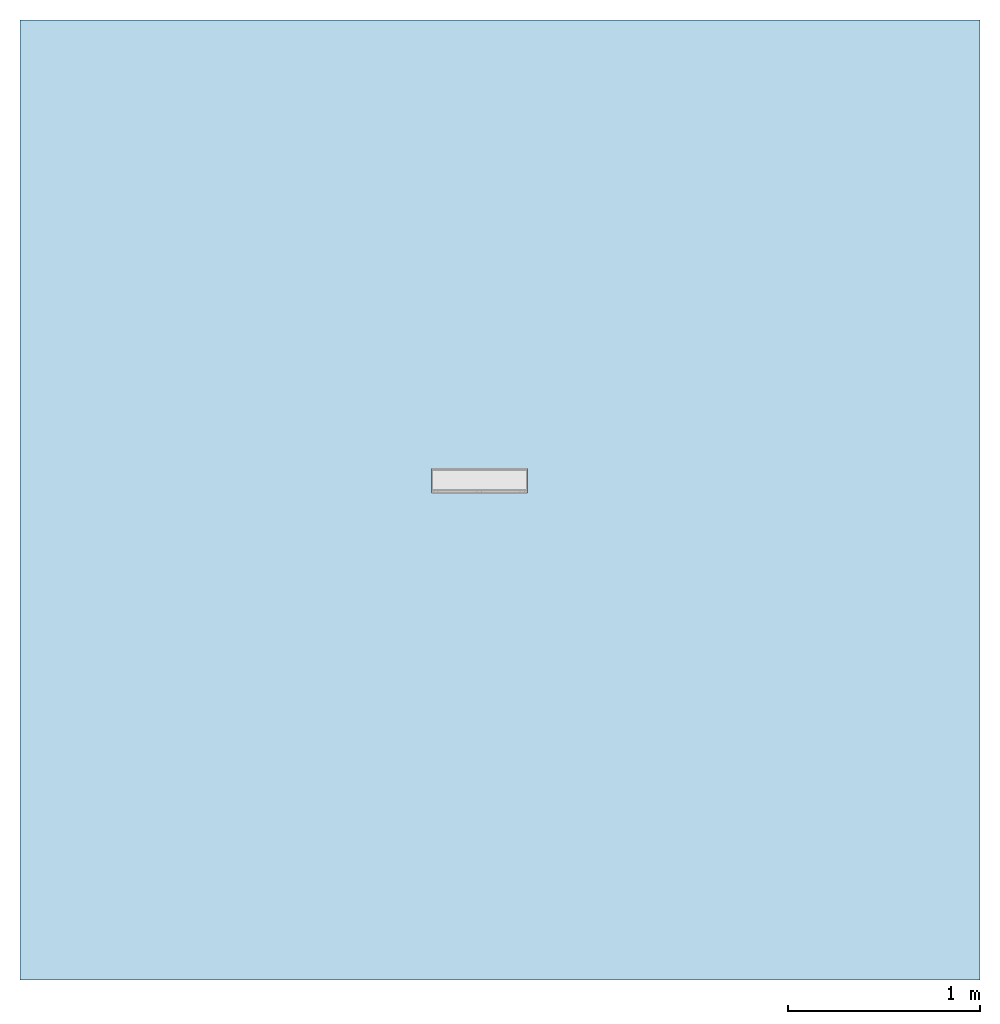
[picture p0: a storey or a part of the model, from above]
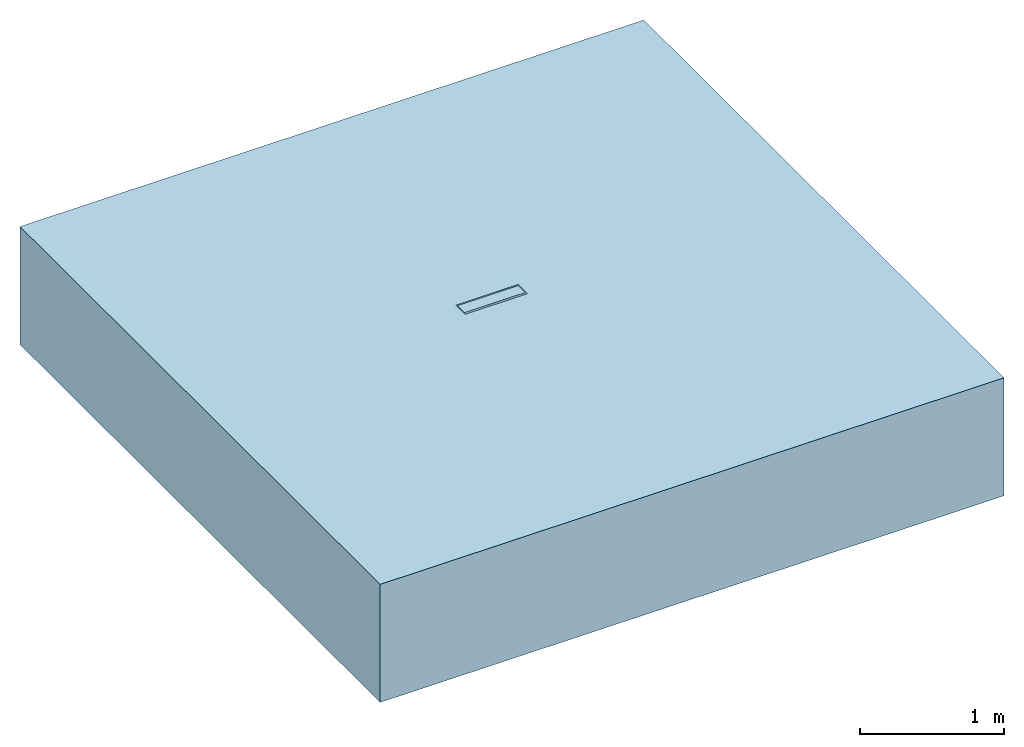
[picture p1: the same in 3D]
Properties of the parts of a building model (IFC2X3)

# File
Description: ViewDefinition [CoordinationView]
File name: 23410 - Universal Sump Unit - 500mm LG.ifc
Time: 2013-10-31T17:35:49
Written by: Autodesk Revit 2013
Made in: 20120221_2030(x64)

# IfcProject, Project Number
LongName: Project Name; Phase: Project Status

# IfcSite, Default
RefLatitude: 42, 21, 30, 344238; RefLongitude: -71, -3, -35, -194702; RefElevation: 0 mm

# IfcBuilding
Pset_BuildingCommon - NumberOfStoreys: 1
Other - Project Address: ## Street City, State Zip; Client Name: Owner; Project Number: Project Number; Project Name: Project Name; Project Issue Date: Issue Date; Project Status: Project Status

# IfcBuildingStorey, Level 1
LongName: Level 1; Elevation: 0 mm
Constraints - Elevation Base: 0; Elevation: 0 mm
Graphics - Color: 0; Symbol: M_Level Head - Circle: M_Level Head - Circle; Symbol at End 1 Default: no; Line Pattern: Center; Symbol at End 2 Default: yes; Line Weight: 1
Identity Data - Building Story: yes; Name: Level 1; Structural: no
Dimensions - Computation Height: 0 mm

# IfcBuildingElementProxy: 23410 - Universal Sump Unit - 500mm LG, Civil-Drainage-Channel-ACO-MultiDrain-M100D-Brickslot-Channel-System:23410 - Universal Sump Unit - 500mm LG:23410 - Universal Sump Unit - 500mm LG:196059
In: Level 1
Material: Vienite® Synthetic Resin Concrete, Phenolic Resin, Plastic, Opaque Black, Steel, Galvanized
Materials and Finishes - Edge Rail Colour: Silver; Channel Colour: Brown; Edge Rail Material: Steel; Channel Material: Vienite® Synthetic Resin Concrete; Edge Rail Finish: Pre-galvanised
Constraints - Level: Level: Level 1; Moves With Nearby Elements: no
Construction - 23460_Load Class C250_Brickslot Grating_Galvanized Steel_1000mm Long: no; 23404_Universal Endcap (Male End): no; 23462_Load Class C250_Brickslot Access Unit_Galvanised Steel_500mm Long: no; 23465_Load Class D400_Brickslot Grating_Galvanized Steel_1000mm Long: no; 23461_Load Class C250_Brickslot Grating_Galvanized Steel_500mm Long: no; 23404_Universal Endcap (Female End): no; 23467_Load Class D400_Brickslot Access Unit_Galvanised Steel_500mm Long: yes; 23466_Load Class D400_Brickslot Grating_Galvanized Steel_500mm Long: no; Constant Depth Junction Channel: no; 23410_Sump Unit: yes; Sloping Channel: no; Shallow Depth Channel with seal: no; Shallow Depth Channel: no; Constant Depth Channel: no
Dimensions - Brickslot Void Length: 1000 mm; Custom_Void_length: 500 mm; FloorCut_Length: -500 mm; Brickslot Void Depth: 6000 mm; EndCap Position: 500 mm; Volume: 16336718 mm3; Brickslot Access Unit Void Bottom Depth: -105 mm; Brickslot Access Unit Void Depth: 0 mm; Length: 1000 mm; FloorCut_Depth: 635 mm; Depth: 150 mm; SlopingOverallDepth: 245 mm; FloorCut_Width: 135 mm; GratingLength: -1000 mm; InvDepth: 80 mm; Floor Cut Gap: 105 mm; ShallowOverallDepth: 75 mm; SlopingEndInvertDepth: 180 mm; Brickslot Access Unit Floor Cut Length: 500 mm; EndCap_Height: 250 mm; Access_Custom_Void_Length: 0 mm; Length Drain: -500 mm; ShallowInvDepth: 55 mm; SlopingEndOverallDepth: 250 mm; SlopingInvertDepth: 175 mm
Phasing - Phase Created: New Construction
Pset_BuildingElementProxyCommon - Reference: 23410 - Universal Sump Unit - 500mm LG
Model Properties - Brickslot Access Unit Product code 23467: Load Class D400 - Brickslot Access Unit Galvanised Steel - 500mm long x 105mm high - 10mm Slot - Intake area - 10000mm²/m - 6.4 Kg; Brickslot Access Unit Product code 23462: Load Class C250 - Brickslot Access Unit Galvanised Steel - 500mm long x 105mm high - 10mm Slot - Intake area - 10000mm²/m - 6.4 Kg; Brickslot Grating Product code 23465: N/A; Brickslot Grating Product code 23466: N/A; End Cap Product code 23404: No 306 Universal End Cap - 135mm wide x 300mm long - Spigot Ø110mm x 50mm long - Silver - Polypropylene - 0.16kg; Brickslot Grating Product code 23460: N/A; Brickslot Grating Product code 23461: N/A
Identity Data - e-mail Sales: customersupport@aco.co.uk; Assembly Code: D2040; Product brochure: http://www.aco.co.uk/download.php?id=173; OmniClass Title: Rainwater Removal; Installation guidelines: http://www.aco.co.uk/download.php?id=173; Watermarked With: BIM Manager Premium Suite; OmniClass Number: 23.70.50.24; e-mail Technical: technical@aco.co.uk; Model Description: Channel drainage system; URL: www.aco.co.uk; Watermark 2: This file is water marked and users are prohibited to reproduce, adapt, distribute this information; Address: ACO Business Park, Hitchin Road, Shefford, Bedfordshire, United Kingdom SG17 5TE; Maintenance guidelines: http://www.aco.co.uk/download.php?id=173; Type Comments: ACO MultiDrain M100D Sump Unit 500mm Long; Model: ACO MultiDrain MD Brickslot- M100D; Telephone: +44 (0)1462 816666; Product Page URL: http://www.aco.co.uk/product_detail.php?id=58; Watermark 1: This file is the property of ACO Technologies PLC; Assembly Description: Rain Water Drainage; Price: POA - contact ACO; Cost: 0; Fax: +44 (0)1462 815895; Product Code: 23410; Manufacturer: ACO Technologies plc - ACO Water Management Division
General - SerialNumber: 0; TagNumber: 0
Data - Pre-formed Outlet Ø: N/A; Load Class: A 15 - D 400; ACO Hydraulic Design Software: http://www.acodesign.co.uk; Product Standard: BS EN 1433:2002, CE marked; Product Dimensions: 500mm x 135mm x 635mm (LxWxH); Concrete Surround Volume - Load Class A 15 - Concrete Pavement: N/A; Hydraulic Performance: http://www.aco.co.uk/download.php?id=173; Product Weight: 32.8 Kg; Invert Depth: 615mm; Channel C.S.A: N/A; Installation - Concrete Grade: Refer to brochure; Concrete Surround Volume - Load Class B 125 - C 250 - Concrete Pavement: N/A; Concrete Surround Volume - Load Class D 400 - Concrete Pavement: N/A
Other - Created By: www.aco.co.uk; Watermarked By: www.aco.co.uk; Revision: 1
Green Building Properties - Channel Recyclable: Fully recyclable; Edge Rail Recycled Material Content: Between 40% - 90%; Edge Rail Recyclable: Fully recyclable; Channel Recycled Material Content: 20% minimum

# IfcOpeningElement: Recess (2)
In: Level 1
Structural - Structural: no; Enable Analytical Model: no
Dimensions - Area: 25000000 mm2; Volume: 24955543390 mm3; Perimeter: 20000 mm; Thickness: 1000 mm
Constraints - Level: Level: Level 1; Height Offset From Level: 0 mm; Room Bounding: yes; Related to Mass: no
Phasing - Phase Created: New Construction
Construction - Default Thickness: 1000 mm; Function: 0
Materials and Finishes - Structural Material: Earth
Analytical Properties - Thermal Resistance (R): 1.19474; Thermal mass: 1359800; Absorptance: 0.1; Roughness: 1; Heat Transfer Coefficient (U): 0.837
Graphics - Coarse Scale Fill Color: 0

# IfcSlab: Floor:Generic Floor - 1000mm, Floor:Generic Floor - 1000mm:193825
In: Level 1
PredefinedType: FLOOR; Material: Earth 1000 mm
Structural - Structural: no; Enable Analytical Model: no
Dimensions - Area: 25000000 mm2; Volume: 24955543390 mm3; Perimeter: 20000 mm; Thickness: 1000 mm
Constraints - Level: Level: Level 1; Height Offset From Level: 0 mm; Room Bounding: yes; Related to Mass: no
Phasing - Phase Created: New Construction
Pset_SlabCommon - Reference: Generic Floor - 1000mm; IsExternal: no; LoadBearing: yes
Construction - Default Thickness: 1000 mm; Function: 0
Materials and Finishes - Structural Material: Earth
Analytical Properties - Thermal Resistance (R): 1.19474; Thermal mass: 1359800; Absorptance: 0.1; Roughness: 1; Heat Transfer Coefficient (U): 0.837
Graphics - Coarse Scale Fill Color: 0
